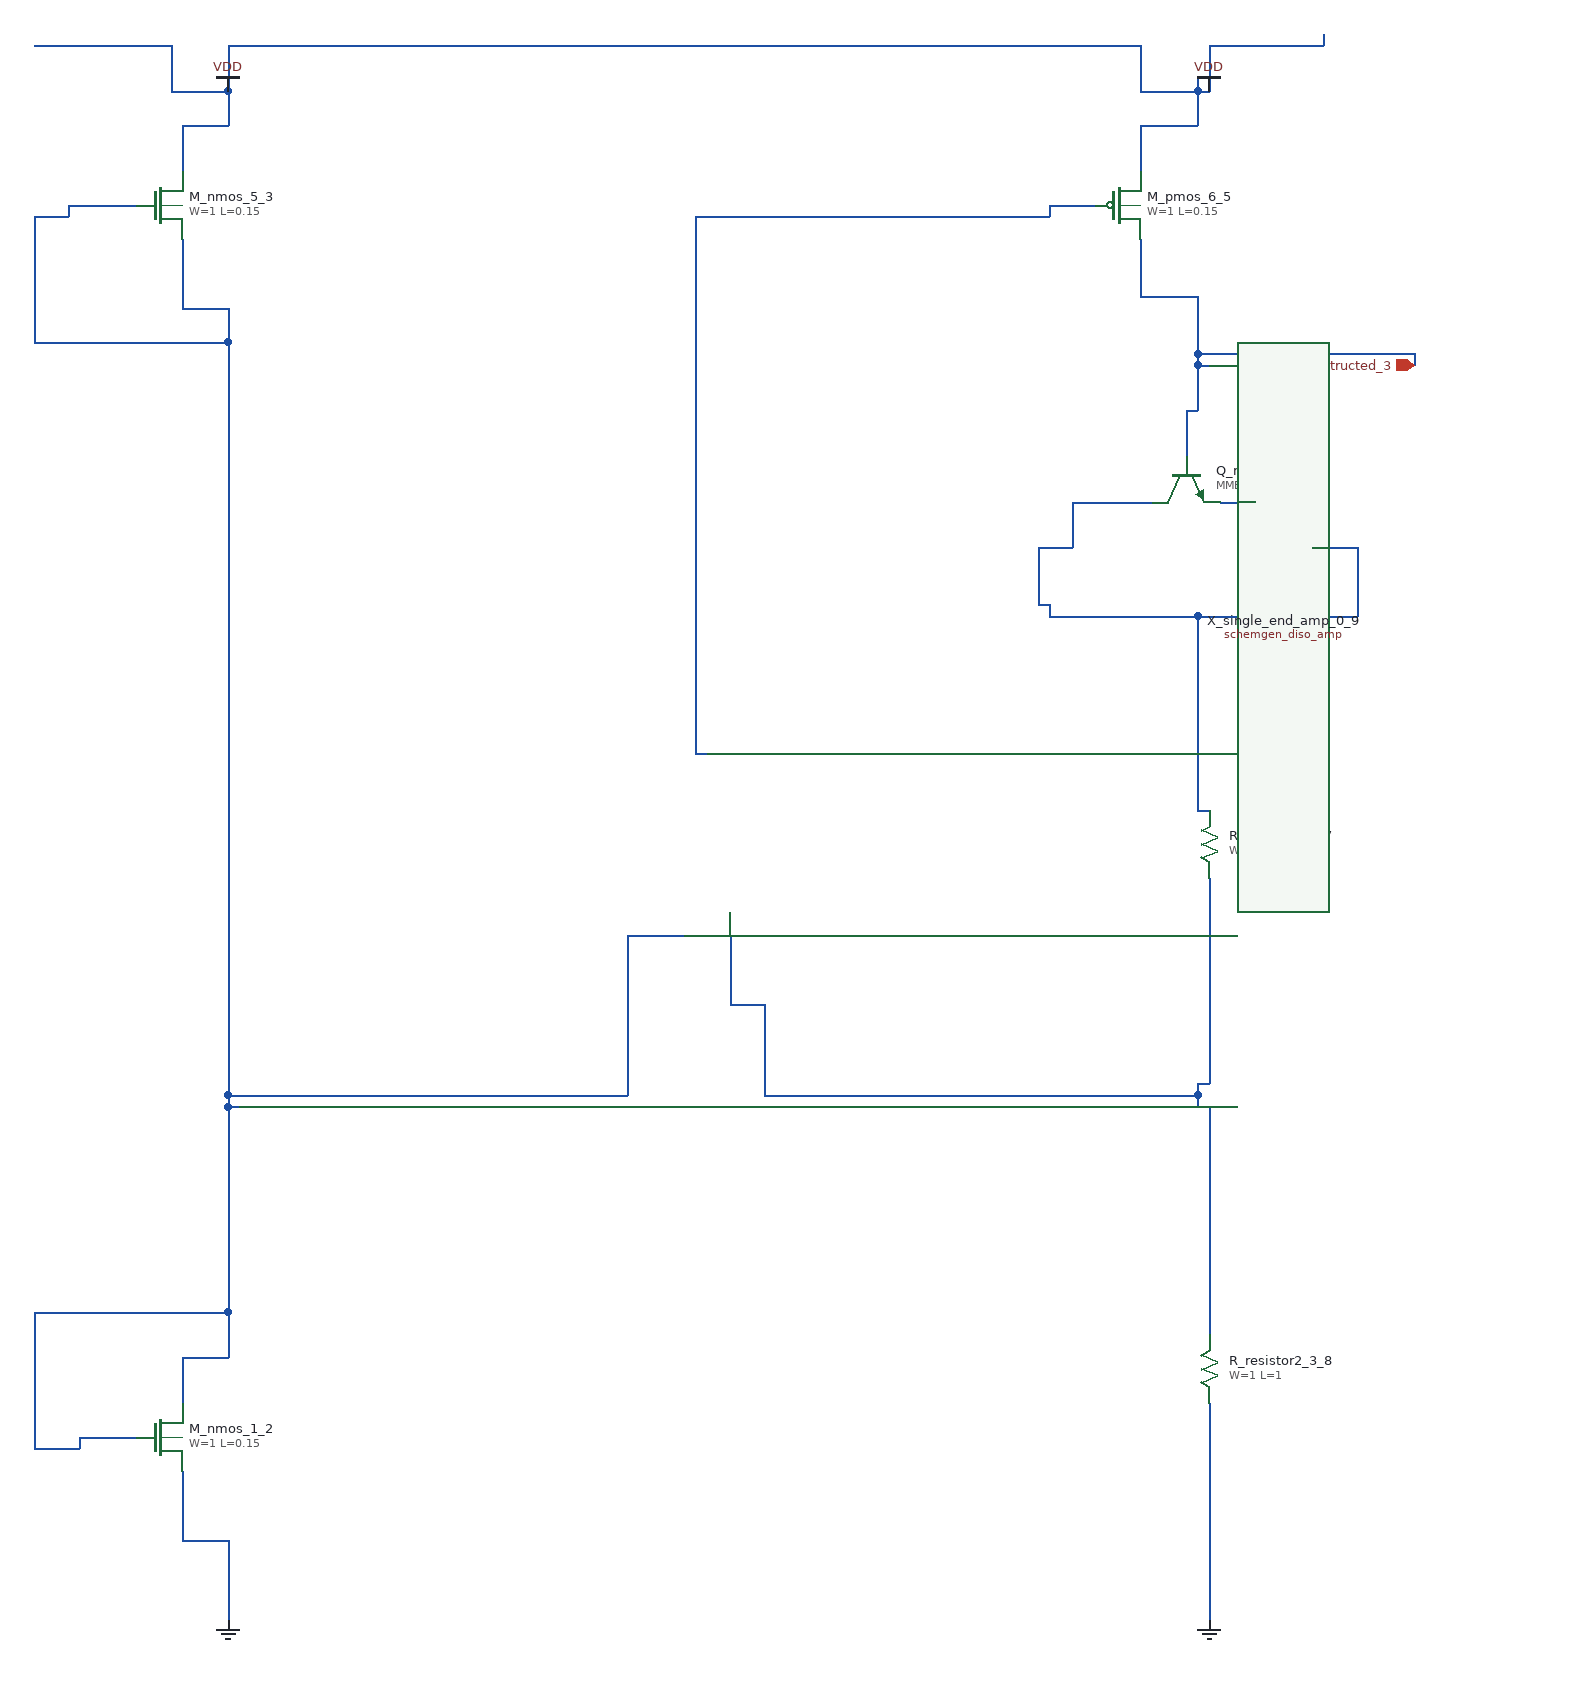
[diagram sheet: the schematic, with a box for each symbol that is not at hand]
v {xschem version=3.4.8 file_version=1.2}
G {}
K {}
V {}
S {}
E {}
C {devices/gnd.sym} 340 1540 0 0 {name="l_gnd_4_0" lab="GND"}
C {devices/gnd.sym} 1200 1540 0 0 {name="l_gnd_9_1" lab="GND"}
C {sky130_fd_pr/nfet3_01v8.sym} 280 1380 0 0 {name="M_nmos_1_2"
W=1
L=0.15
body=GND
nf=1
mult=1
ad="expr('int((@nf + 1)/2) * @W / @nf * 0.29')"
pd="expr('2*int((@nf + 1)/2) * (@W / @nf + 0.29)')"
as="expr('int((@nf + 2)/2) * @W / @nf * 0.29')"
ps="expr('2*int((@nf + 2)/2) * (@W / @nf + 0.29)')"
nrd="expr('0.29 / @W ')" nrs="expr('0.29 / @W ')"
sa=0 sb=0 sd=0
model=nfet_01v8
spiceprefix=X
}
C {sky130_fd_pr/nfet3_01v8.sym} 280 300 2 1 {name="M_nmos_5_3"
W=1
L=0.15
body=GND
nf=1
mult=1
ad="expr('int((@nf + 1)/2) * @W / @nf * 0.29')"
pd="expr('2*int((@nf + 1)/2) * (@W / @nf + 0.29)')"
as="expr('int((@nf + 2)/2) * @W / @nf * 0.29')"
ps="expr('2*int((@nf + 2)/2) * (@W / @nf + 0.29)')"
nrd="expr('0.29 / @W ')" nrs="expr('0.29 / @W ')"
sa=0 sb=0 sd=0
model=nfet_01v8
spiceprefix=X
}
C {devices/npn.sym} 1180 540 3 1 {name="Q_npn_8_4"
model=MMBT2222
device=MMBT2222
footprint=SOT23
area=1
m=1}
C {sky130_fd_pr/pfet3_01v8.sym} 1120 300 0 0 {name="M_pmos_6_5"
W=1
L=0.15
body=VDD
nf=1
mult=1
ad="expr('int((@nf + 1)/2) * @W / @nf * 0.29')"
pd="expr('2*int((@nf + 1)/2) * (@W / @nf + 0.29)')"
as="expr('int((@nf + 2)/2) * @W / @nf * 0.29')"
ps="expr('2*int((@nf + 2)/2) * (@W / @nf + 0.29)')"
nrd="expr('0.29 / @W ')" nrs="expr('0.29 / @W ')"
sa=0 sb=0 sd=0
model=pfet_01v8
spiceprefix=X
}
C {devices/ipin.sym} 1380 440 0 0 {name="p_port_7_6" lab="PORT_reconstructed_3"}
C {sky130_fd_pr/res_generic_po.sym} 1200 860 2 0 {name="R_resistor2_2_7"
W=1
L=1
model=res_generic_po
spiceprefix=X
mult=1}
C {sky130_fd_pr/res_generic_po.sym} 1200 1320 2 0 {name="R_resistor2_3_8"
W=1
L=1
model=res_generic_po
spiceprefix=X
mult=1}
C {schemgen_diso_amp.sym} 760 860 1 1 {name="X_single_end_amp_0_9"}
C {devices/vdd.sym} 1200 200 0 0 {name="l_vdd_10_10" lab="VDD"}
C {devices/vdd.sym} 340 200 0 0 {name="l_vdd_11_11" lab="VDD"}
N 300 1470 340 1470 {}
N 300 1470 300 1410 {}
N 340 1540 340 1470 {}
N 1200 1540 1200 1350 {}
N 1190 830 1200 830 {}
N 1060 660 1190 660 {}
N 1190 660 1230 660 {}
N 1230 660 1330 660 {}
N 1050 650 1060 650 {}
N 1050 600 1080 600 {}
N 1290 600 1330 600 {}
N 1080 560 1150 560 {}
N 1210 560 1230 560 {}
N 1230 560 1240 560 {}
N 1050 650 1050 600 {}
N 1060 660 1060 650 {}
N 1080 600 1080 560 {}
N 1190 830 1190 660 {}
N 1230 660 1230 560 {}
N 1330 660 1330 600 {}
N 300 230 340 230 {}
N 1140 230 1190 230 {}
N 290 200 340 200 {}
N 1140 200 1190 200 {}
N 1190 200 1200 200 {}
N 170 160 290 160 {}
N 340 160 1140 160 {}
N 1200 160 1300 160 {}
N 290 200 290 160 {}
N 300 270 300 230 {}
N 340 230 340 200 {}
N 340 200 340 160 {}
N 1140 270 1140 230 {}
N 1140 200 1140 160 {}
N 1190 230 1190 200 {}
N 1190 200 1190 190 {}
N 1200 200 1200 160 {}
N 1300 160 1300 150 {}
N 1180 480 1190 480 {}
N 1190 440 1200 440 {}
N 1190 430 1380 430 {}
N 1140 380 1190 380 {}
N 1140 380 1140 330 {}
N 1180 520 1180 480 {}
N 1190 480 1190 440 {}
N 1190 440 1190 430 {}
N 1190 430 1190 380 {}
N 1380 440 1380 430 {}
N 750 780 760 780 {}
N 750 310 1060 310 {}
N 1060 300 1100 300 {}
N 750 780 750 310 {}
N 1060 310 1060 300 {}
N 1190 1090 1200 1090 {}
N 810 1080 1190 1080 {}
N 1190 1070 1200 1070 {}
N 780 1000 810 1000 {}
N 780 1000 780 940 {}
N 810 1080 810 1000 {}
N 1190 1090 1190 1080 {}
N 1190 1080 1190 1070 {}
N 1200 1290 1200 1090 {}
N 1200 1070 1200 890 {}
N 170 1390 210 1390 {}
N 210 1380 260 1380 {}
N 300 1310 340 1310 {}
N 170 1270 340 1270 {}
N 340 1090 350 1090 {}
N 340 1080 690 1080 {}
N 690 940 740 940 {}
N 170 420 340 420 {}
N 300 390 340 390 {}
N 170 310 200 310 {}
N 200 300 260 300 {}
N 170 1390 170 1270 {}
N 170 420 170 310 {}
N 200 310 200 300 {}
N 210 1390 210 1380 {}
N 300 1350 300 1310 {}
N 300 390 300 330 {}
N 340 1310 340 1270 {}
N 340 1270 340 1090 {}
N 340 1090 340 1080 {}
N 340 1080 340 420 {}
N 340 420 340 390 {}
N 690 1080 690 940 {}
